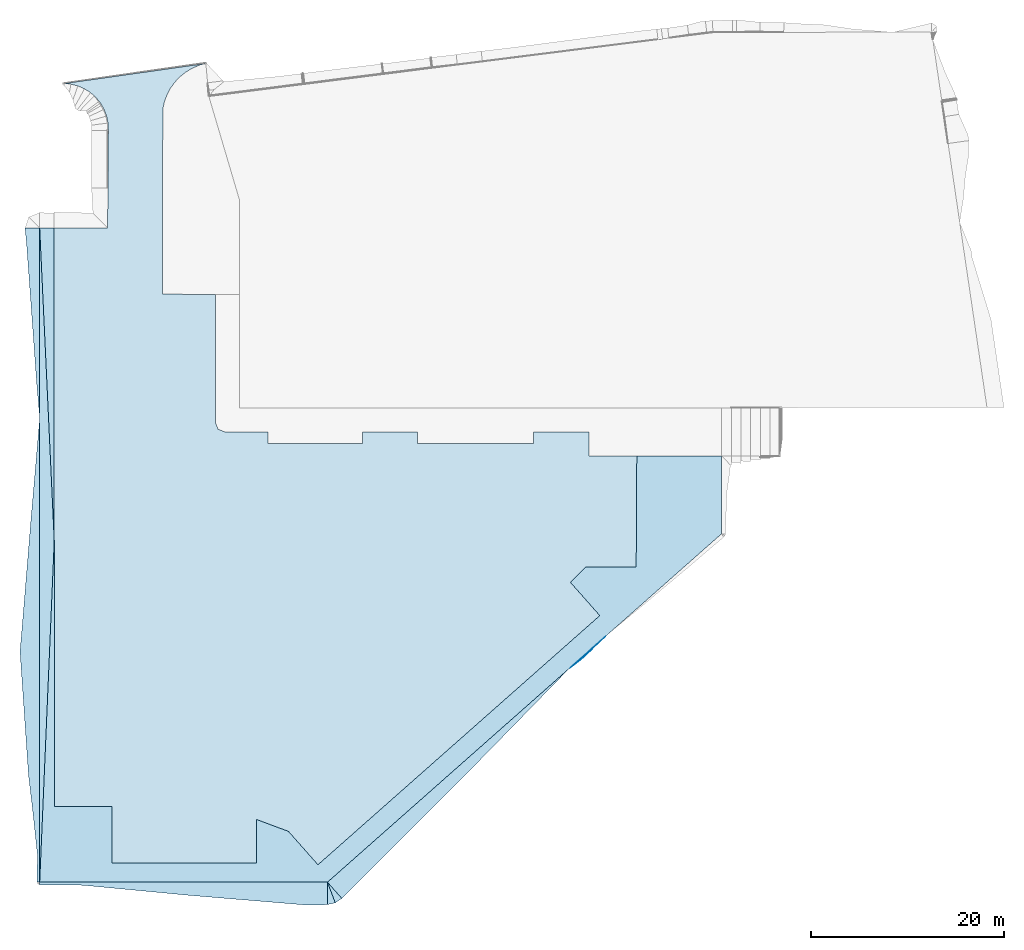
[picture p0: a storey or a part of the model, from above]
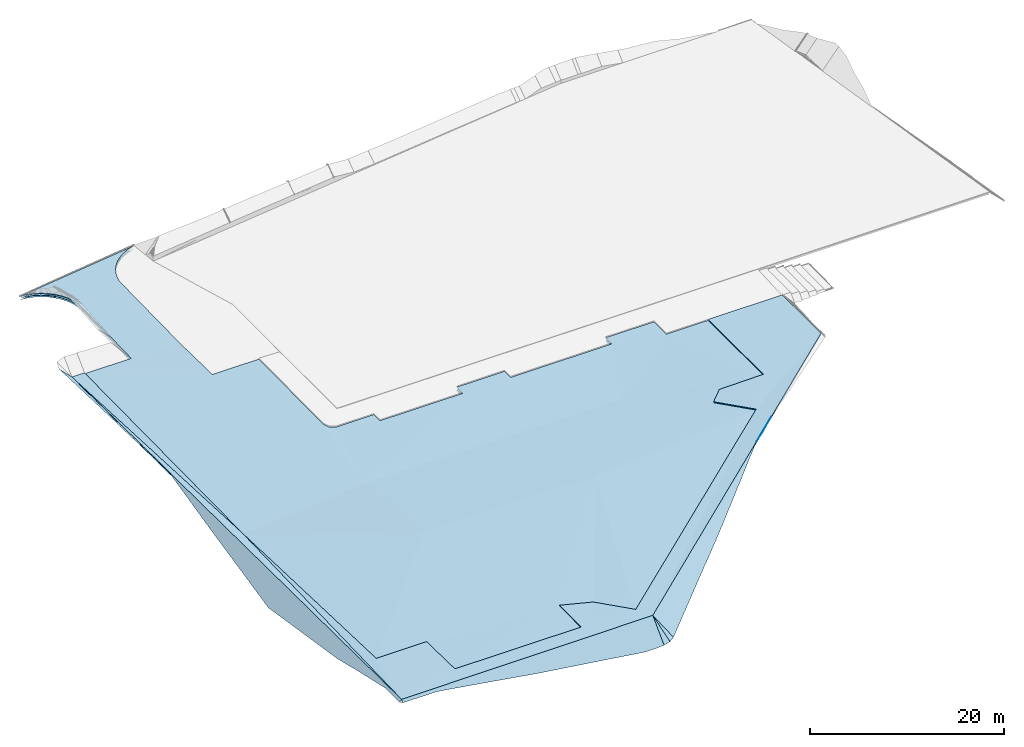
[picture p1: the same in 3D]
Properties of the parts of a building model (IFC2X3)

# File
Description: IFC2X3
File name: Projet VRD 8.0.2
Time: 2015-11-03T10:04:04
Made in: IfcPlusPlus

# IfcSlab (116)
In: VRD
PredefinedType: USERDEFINED
Name | Surface Horizontale (m2) | Surface Selon la pente (m2) | Numéro de PTF | Code de PTF | Volume Déblais (m3) | Volume Remblais (m3) | Epaisseur Décaissement (m)
PJ FINI n°4 (Terre Végétale) | 424.434 | 431.042 | PSET-MENSURA - Nom couche: Terre Végétale; Epaisseur couche: 0.2 m; Volume couche: 86.2085 m3
PJ FINI n°4 | 424.434 | 431.042 | 4 | Espace vert | 306.834 | 1426.62 | 0.2 | PSET-MENSURA - Epaisseur < Terre Végétale >: 0.2 m; Volume < Terre Végétale >: 86.2085 m3
PJ FINI n°2 (Enrobés) | 2526.36 | 2529.97 | PSET-MENSURA - Nom couche: Enrobés; Epaisseur couche: 0.06 m; Volume couche: 151.798 m3
PJ FINI n°2 (GB 0/14) | 2526.36 | 2529.97 | PSET-MENSURA - Nom couche: GB 0/14; Epaisseur couche: 0.2 m; Volume couche: 505.994 m3
PJ FINI n°2 (GNT 0/31.5) | 2526.36 | 2529.97 | PSET-MENSURA - Nom couche: GNT 0/31.5; Epaisseur couche: 0.2 m; Volume couche: 505.994 m3
PJ FINI n°2 | 2526.36 | 2529.97 | 2 | Voirie légère | 6543.72 | 7370.1 | 0.46 | PSET-MENSURA - Epaisseur < Enrobés >: 0.06 m; Volume < Enrobés >: 151.798 m3; Epaisseur < GB 0/14 >: 0.2 m; Volume < GB 0/14 >: 505.994 m3; Epaisseur < GNT 0/31.5 >: 0.2 m; Volume < GNT 0/31.5 >: 505.994 m3
PJ FINI n°9 | 0.177327 | 0.250778 | 9 | Talus | 0 | 0.107623 | 0
PJ FINI n°3 (Enrobés) | 220.571 | 220.807 | PSET-MENSURA - Nom couche: Enrobés; Epaisseur couche: 0.04 m; Volume couche: 8.83226 m3
PJ FINI n°3 (Tout venant 0/31.5) | 220.571 | 220.807 | PSET-MENSURA - Nom couche: Tout venant 0/31.5; Epaisseur couche: 0.2 m; Volume couche: 44.1613 m3
PJ FINI n°3 | 220.571 | 220.807 | 3 | Trottoir | 414.432 | 175.548 | 0.24 | PSET-MENSURA - Epaisseur < Enrobés >: 0.04 m; Volume < Enrobés >: 8.83226 m3; Epaisseur < Tout venant 0/31.5 >: 0.2 m; Volume < Tout venant 0/31.5 >: 44.1613 m3
PJ FINI n°1 (Dallage béton) | 2770.14 | 2770.14 | PSET-MENSURA - Nom couche: Dallage béton; Epaisseur couche: 0.1 m; Volume couche: 277.014 m3
PJ FINI n°1 (Hérisson 0/31.5) | 2770.14 | 2770.14 | PSET-MENSURA - Nom couche: Hérisson 0/31.5; Epaisseur couche: 0.2 m; Volume couche: 554.028 m3
PJ FINI n°1 | 2770.14 | 2770.14 | 1 | Bâtiment | 18726.7 | 4430.7 | 0.3 | PSET-MENSURA - Epaisseur < Dallage béton >: 0.1 m; Volume < Dallage béton >: 277.014 m3; Epaisseur < Hérisson 0/31.5 >: 0.2 m; Volume < Hérisson 0/31.5 >: 554.028 m3
PJ FINI n°10 | 0.0257739 | 0.037981 | 10 | Talus | 0 | 0.0139178 | 0
PJ FINI n°29 | 10.3937 | 14.5292 | 29 | Talus | 58.6563 | 0.0150668 | 0
PJ FINI n°8 (Terre Végétale) | 156.105 | 156.153 | PSET-MENSURA - Nom couche: Terre Végétale; Epaisseur couche: 0.2 m; Volume couche: 31.2306 m3
PJ FINI n°8 | 156.105 | 156.153 | 8 | Espace vert | 1540.66 | 0 | 0.2 | PSET-MENSURA - Epaisseur < Terre Végétale >: 0.2 m; Volume < Terre Végétale >: 31.2306 m3
PJ FINI n°11 | 0.032488 | 0.3265 | 11 | Talus | 0.370494 | 0 | 0
PJ FINI n°12 | 0.678896 | 0.959016 | 12 | Talus | 3.63749 | 0 | 0
PJ FINI n°13 | 4.72726 | 6.68536 | 13 | Talus | 17.3875 | 0 | 0
PJ FINI n°14 | 5.38664 | 7.61859 | 14 | Talus | 27.1608 | 0 | 0
PJ FINI n°109 | 1.16169 | 1.91862 | 109 | Talus | 6.81888 | 0 | 0
PJ FINI n°15 | 2.14014 | 3.05419 | 15 | Talus | 11.5781 | 0 | 0
PJ FINI n°16 | 0.0325726 | 0.327351 | 16 | Talus | 0.375036 | 0 | 0
PJ FINI n°17 | 25.8494 | 36.5566 | 17 | Talus | 0 | 120.832 | 0
PJ FINI n°18 | 0.230513 | 2.31662 | 18 | Talus | 2.78704 | 0 | 0
PJ FINI n°19 | 1.61501 | 16.2306 | 19 | Talus | 18.5583 | 0 | 0
PJ FINI n°20 | 0.0394466 | 0.396434 | 20 | Talus | 0.461958 | 0 | 0
PJ FINI n°21 | 2.72466 | 3.87465 | 21 | Talus | 13.6249 | 0 | 0
PJ FINI n°22 | 0.338778 | 0.479106 | 22 | Talus | 0.0532122 | 0 | 0
PJ FINI n°23 | 0.316463 | 0.448198 | 23 | Talus | 1.78425 | 0 | 0
PJ FINI n°24 | 1.70072 | 2.40519 | 24 | Talus | 5.62303 | 0 | 0
PJ FINI n°25 | 0.0284126 | 0.0401988 | 25 | Talus | 0.142428 | 0 | 0
PJ FINI n°110 | 0.931706 | 1.48041 | 110 | Talus | 5.50847 | 0.000643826 | 0
PJ FINI n°26 | 1.09085 | 1.54276 | 26 | Talus | 2.57373 | 0 | 0
PJ FINI n°27 | 0.539409 | 0.762839 | 27 | Talus | 0 | 0.994353 | 0
PJ FINI n°28 | 1.88616 | 2.66744 | 28 | Talus | 0 | 1.48703 | 0
PJ FINI n°30 | 19.6956 | 27.8538 | 30 | Talus | 102.521 | 0 | 0
PJ FINI n°31 | 38.3429 | 54.2252 | 31 | Talus | 0 | 196.143 | 0
PJ FINI n°32 | 10.1546 | 14.3806 | 32 | Talus | 51.1912 | 0 | 0
PJ FINI n°33 | 0.00345396 | 0.00508984 | 33 | Talus | 0 | 0.00247217 | 0
PJ FINI n°34 | 0.146854 | 1.47586 | 34 | Talus | 1.76045 | 0 | 0
PJ FINI n°35 | 0.0290041 | 0.0410181 | 35 | Talus | 0.146563 | 0 | 0
PJ FINI n°36 | 51.8353 | 73.3079 | 36 | Talus | 0 | 217.459 | 0
PJ FINI n°37 | 4.71765 | 6.67202 | 37 | Talus | 0 | 9.29557 | 0
PJ FINI n°38 | 5.07711 | 7.18012 | 38 | Talus | 25.5699 | 0 | 0
PJ FINI n°39 | 0.3698 | 0.523 | 39 | Talus | 0.163363 | 0 | 0
PJ FINI n°40 | 0.247844 | 0.35829 | 40 | Talus | 1.45594 | 0 | 0
PJ FINI n°41 | 2.50097 | 3.55592 | 41 | Talus | 13.8837 | 0 | 0
PJ FINI n°42 | 0.98296 | 1.39012 | 42 | Talus | 0 | 0.678616 | 0
PJ FINI n°83 | 5 | 5 | 83 | Marche | 0 | 36.5554 | 0
PJ FINI n°84 | 5 | 5 | 84 | Marche | 0 | 31.472 | 0
PJ FINI n°85 | 5 | 5 | 85 | Marche | 0 | 25.9641 | 0
PJ FINI n°87 | 5 | 5 | 87 | Marche | 0 | 13.0598 | 0
PJ FINI n°43 | 0.324413 | 0.458887 | 43 | Talus | 1.74232 | 0 | 0
PJ FINI n°86 | 5 | 5 | 86 | Marche | 0 | 19.8677 | 0
PJ FINI n°88 | 5 | 5 | 88 | Marche | 0.0187395 | 5.79525 | 0
PJ FINI n°44 | 0.00230563 | 0.0231714 | 44 | Talus | 0.0241306 | 0 | 0
PJ FINI n°45 | 0.037447 | 0.0535581 | 45 | Talus | 0 | 0.0319418 | 0
PJ FINI n°46 | 0.0129242 | 0.0182776 | 46 | Talus | 0 | 0.0188838 | 0
PJ FINI n°47 | 1.00491 | 1.41973 | 47 | Talus | 5.45041 | 0 | 0
PJ FINI n°48 | 0.0105744 | 0.0149544 | 48 | Talus | 0 | 0.0313862 | 0
PJ FINI n°49 | 0.709667 | 1.00362 | 49 | Talus | 0 | 1.67993 | 0
PJ FINI n°50 | 3.65725 | 5.17238 | 50 | Talus | 0 | 3.26764 | 0
PJ FINI n°51 | 39.4388 | 55.7776 | 51 | Talus | 0 | 182.369 | 0
PJ FINI n°52 | 0.0905427 | 0.909941 | 52 | Talus | 1.07957 | 0 | 0
PJ FINI n°53 | 0.902219 | 1.32953 | 53 | Talus | 2.6373 | 0 | 0
PJ FINI n°54 | 0.00352479 | 0.00498481 | 54 | Talus | 0 | 0.0263972 | 0
PJ FINI n°55 | 0.860553 | 1.26813 | 55 | Talus | 2.5155 | 0 | 0
PJ FINI n°56 | 0.942723 | 1.34432 | 56 | Talus | 0 | 4.25727 | 0
PJ FINI n°57 | 2.81264 | 3.97684 | 57 | Talus | 14.1538 | 0 | 0
PJ FINI n°58 | 0.496641 | 0.702356 | 58 | Talus | 0 | 1.79726 | 0
PJ FINI n°59 | 0.171767 | 0.242915 | 59 | Talus | 0.920231 | 0 | 0
PJ FINI n°60 | 15.0528 | 21.2884 | 60 | Talus | 43.6329 | 0 | 0
PJ FINI n°61 | 8.63193 | 12.2074 | 61 | Talus | 45.0484 | 0 | 0
PJ FINI n°62 | 0.46009 | 0.650734 | 62 | Talus | 2.99087 | 0 | 0
PJ FINI n°63 | 0.695072 | 0.982952 | 63 | Talus | 3.7107 | 0 | 0
PJ FINI n°64 | 2.20714 | 3.1213 | 64 | Talus | 13.3094 | 0 | 0
PJ FINI n°65 | 6.00393 | 8.49045 | 65 | Talus | 22.6001 | 0 | 0
PJ FINI n°66 | 2.77479 | 3.92452 | 66 | Talus | 16.8325 | 0 | 0
PJ FINI n°67 | 0.0360488 | 0.362286 | 67 | Talus | 0.416705 | 0 | 0
PJ FINI n°68 | 0.158852 | 0.224952 | 68 | Talus | 1.39163 | 0 | 0
PJ FINI n°69 | 0.822057 | 1.16255 | 69 | Talus | 5.25884 | 0 | 0
PJ FINI n°70 | 2.34593 | 3.31765 | 70 | Talus | 10.0789 | 0 | 0
PJ FINI n°71 | 0.175845 | 0.248683 | 71 | Talus | 0 | 0.134132 | 0
PJ FINI n°72 | 5.38819 | 7.64867 | 72 | Talus | 31.2654 | 0 | 0
PJ FINI n°73 | 0.0578862 | 0.581749 | 73 | Talus | 0.661418 | 0 | 0
PJ FINI n°74 | 1.01404 | 1.43274 | 74 | Talus | 5.50064 | 0 | 0
PJ FINI n°75 | 2.54347 | 3.59702 | 75 | Talus | 16.3652 | 0 | 0
PJ FINI n°76 | 9.64332 | 13.6366 | 76 | Talus | 37.5761 | 0 | 0
PJ FINI n°77 | 0.109052 | 1.09596 | 77 | Talus | 1.17761 | 0 | 0
PJ FINI n°78 | 7.62935 | 10.7895 | 78 | Talus | 35.3903 | 0 | 0
PJ FINI n°79 | 0.511133 | 0.723224 | 79 | Talus | 2.74778 | 0 | 0
PJ FINI n°80 | 2.30454 | 3.28983 | 80 | Talus | 12.8331 | 0 | 0
PJ FINI n°81 | 0.000203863 | 0.000300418 | 81 | Talus | 0.00000870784 | 0 | 0
PJ FINI n°82 | 0.279069 | 0.394681 | 82 | Talus | 0.0625144 | 0 | 0
PJ FINI n°89 | 0.0332545 | 0.047029 | 89 | Talus | 0.00293206 | 0 | 0
PJ FINI n°90 | 0.781087 | 1.10467 | 90 | Talus | 0.956955 | 0 | 0
PJ FINI n°91 | 1.10902 | 1.56949 | 91 | Talus | 5.83965 | 0 | 0
PJ FINI n°92 | 0.0288768 | 0.290209 | 92 | Talus | 0.324814 | 0 | 0
PJ FINI n°93 | 0.359487 | 0.508391 | 93 | Talus | 0 | 0.442623 | 0
PJ FINI n°94 | 1.25472 | 1.77453 | 94 | Talus | 4.92804 | 0 | 0
PJ FINI n°95 | 0.000663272 | 0.00098018 | 95 | Talus | 0.00010205 | 0 | 0
PJ FINI n°96 | 0.911614 | 1.29996 | 96 | Talus | 0 | 4.11678 | 0
PJ FINI n°97 | 0.853317 | 1.20683 | 97 | Talus | 4.80531 | 0 | 0
PJ FINI n°98 | 0.00822451 | 0.0116312 | 98 | Talus | 0 | 0.036806 | 0
PJ FINI n°99 | 0.00587465 | 0.00830802 | 99 | Talus | 0 | 0.035143 | 0
PJ FINI n°100 | 0.0257739 | 0.037981 | 100 | Talus | 0 | 0.0139178 | 0
PJ FINI n°101 | 0.000872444 | 0.00145871 | 101 | Talus | 0.0000195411 | 0 | 0
PJ FINI n°102 | 0.0394562 | 0.0557981 | 102 | Talus | 0.188895 | 0 | 0
PJ FINI n°103 | 0.0361114 | 0.0516478 | 103 | Talus | 0 | 0.0308025 | 0
PJ FINI n°104 | 0.246028 | 0.359797 | 104 | Talus | 0 | 0.193967 | 0
PJ FINI n°105 | 0.00166117 | 0.00234925 | 105 | Talus | 0.0000709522 | 0 | 0
PJ FINI n°106 | 0.125517 | 0.183558 | 106 | Talus | 0 | 0.0989561 | 0
PJ FINI n°107 | 0.00135809 | 0.00200698 | 107 | Talus | 0.000208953 | 0 | 0
PJ FINI n°108 | 0.000173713 | 0.000255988 | 108 | Talus | 0.00000741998 | 0 | 0
